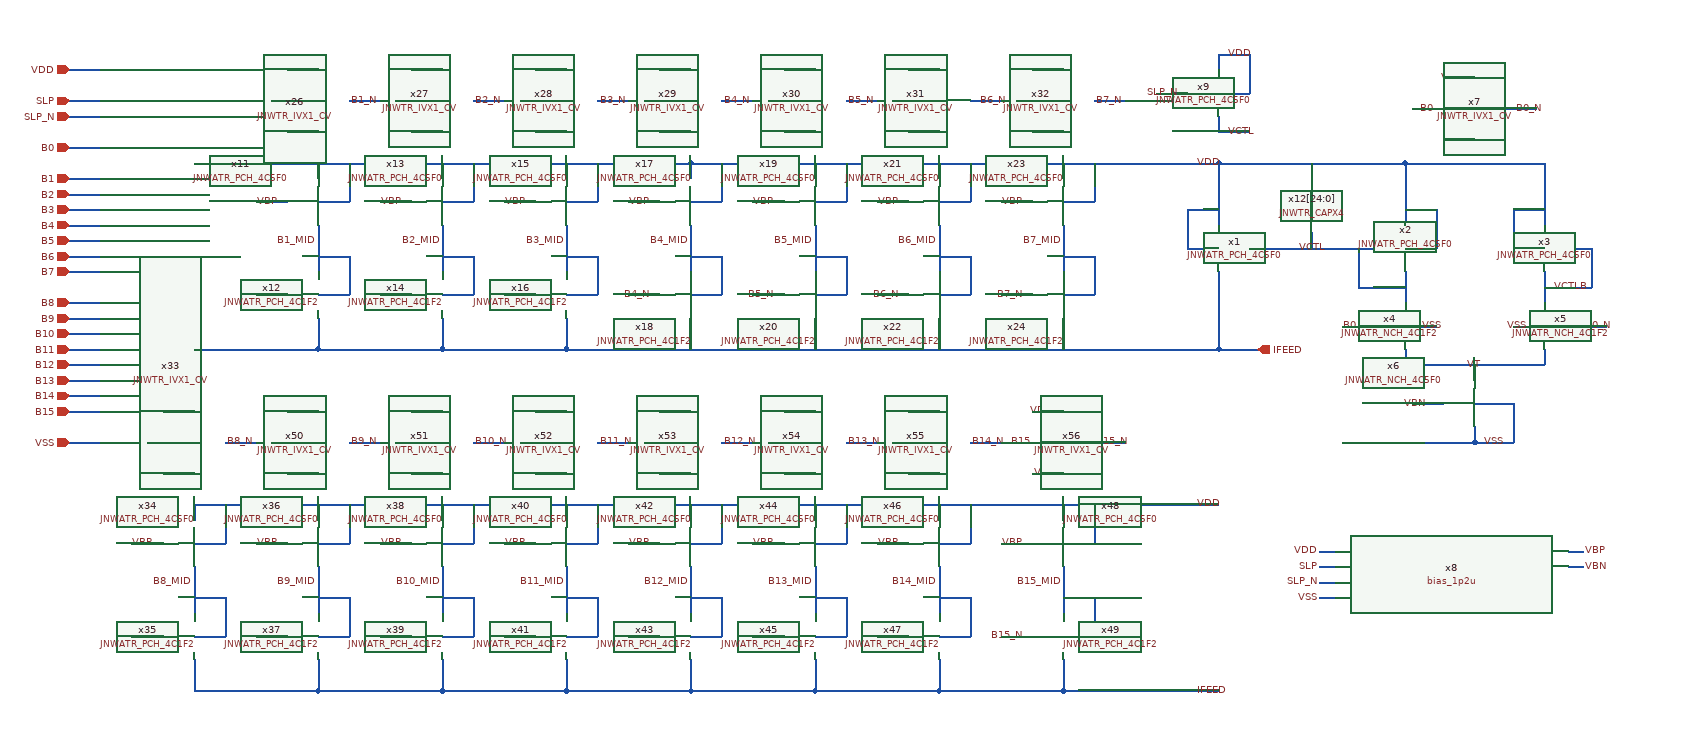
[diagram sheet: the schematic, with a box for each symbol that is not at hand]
v {xschem version=3.4.6 file_version=1.2}
G {}
K {}
V {}
S {}
E {}
N 920 330 960 330 {lab=VBP}
N 1000 280 1000 300 {lab=VDD}
N 1000 360 1000 420 {lab=B4_MID}
N 1000 480 1000 520 {lab=IFEED}
N 920 450 960 450 {lab=B4_N}
N 1000 330 1040 330 {lab=VDD}
N 1040 280 1040 330 {lab=VDD}
N 1000 450 1040 450 {lab=B4_MID}
N 1040 400 1040 450 {lab=B4_MID}
N 1000 400 1040 400 {lab=B4_MID}
N 1020 520 1180 520 {lab=IFEED}
N 1080 330 1120 330 {lab=VBP}
N 1160 280 1160 300 {lab=VDD}
N 1160 360 1160 420 {lab=B5_MID}
N 1160 480 1160 520 {lab=IFEED}
N 1080 450 1120 450 {lab=B5_N}
N 1160 330 1200 330 {lab=VDD}
N 1200 280 1200 330 {lab=VDD}
N 1160 450 1200 450 {lab=B5_MID}
N 1200 400 1200 450 {lab=B5_MID}
N 1160 400 1200 400 {lab=B5_MID}
N 1180 520 1340 520 {lab=IFEED}
N 1240 330 1280 330 {lab=VBP}
N 1320 280 1320 300 {lab=VDD}
N 1320 360 1320 420 {lab=B6_MID}
N 1320 480 1320 520 {lab=IFEED}
N 1240 450 1280 450 {lab=B6_N}
N 1320 330 1360 330 {lab=VDD}
N 1360 280 1360 330 {lab=VDD}
N 1320 450 1360 450 {lab=B6_MID}
N 1360 400 1360 450 {lab=B6_MID}
N 1320 400 1360 400 {lab=B6_MID}
N 1340 520 1500 520 {lab=IFEED}
N 1400 330 1440 330 {lab=VBP}
N 1480 280 1480 300 {lab=VDD}
N 1480 360 1480 420 {lab=B7_MID}
N 1480 480 1480 520 {lab=IFEED}
N 1400 450 1440 450 {lab=B7_N}
N 1480 330 1520 330 {lab=VDD}
N 1520 280 1520 330 {lab=VDD}
N 1480 450 1520 450 {lab=B7_MID}
N 1520 400 1520 450 {lab=B7_MID}
N 1480 400 1520 400 {lab=B7_MID}
N 1000 280 1680 280 {lab=VDD}
N 200 320 240 320 {lab=B2}
N 200 340 240 340 {lab=B3}
N 200 360 240 360 {lab=B4}
N 460 200 480 200 {lab=B1}
N 480 160 520 160 {lab=VDD}
N 480 240 520 240 {lab=VSS}
N 560 200 600 200 {lab=B1_N}
N 620 200 640 200 {lab=B2}
N 640 160 680 160 {lab=VDD}
N 640 240 680 240 {lab=VSS}
N 720 200 760 200 {lab=B2_N}
N 780 200 800 200 {lab=B3}
N 800 160 840 160 {lab=VDD}
N 800 240 840 240 {lab=VSS}
N 880 200 920 200 {lab=B3_N}
N 940 200 960 200 {lab=B4}
N 960 160 1000 160 {lab=VDD}
N 960 240 1000 240 {lab=VSS}
N 1040 200 1080 200 {lab=B4_N}
N 1810 800 1830 800 {lab=SLP}
N 2130 800 2150 800 {lab=VBN}
N 2130 780 2150 780 {lab=VBP}
N 1810 840 1830 840 {lab=VSS}
N 1810 780 1830 780 {lab=VDD}
N 1720 390 1880 390 {lab=VCTL}
N 1680 280 1680 360 {lab=VDD}
N 1500 520 1680 520 {lab=IFEED}
N 1800 370 1800 390 {lab=VCTL}
N 1800 280 1800 300 {lab=VDD}
N 1680 280 1920 280 {lab=VDD}
N 1920 280 1920 360 {lab=VDD}
N 1920 390 1960 390 {lab=VDD}
N 1960 340 1960 390 {lab=VDD}
N 1920 340 1960 340 {lab=VDD}
N 1860 390 1860 440 {lab=VCTL}
N 1860 440 1920 440 {lab=VCTL}
N 1920 420 1920 460 {lab=VCTL}
N 2140 390 2160 390 {lab=VCTLB}
N 2100 280 2100 360 {lab=VDD}
N 2060 390 2100 390 {lab=VDD}
N 2060 340 2060 390 {lab=VDD}
N 2160 390 2160 440 {lab=VCTLB}
N 2100 440 2160 440 {lab=VCTLB}
N 2100 420 2100 460 {lab=VCTLB}
N 1920 280 2100 280 {lab=VDD}
N 2060 340 2100 340 {lab=VDD}
N 1680 420 1680 520 {lab=IFEED}
N 2060 490 2100 490 {lab=VSS}
N 1920 490 1960 490 {lab=VSS}
N 1920 520 1920 540 {lab=VT}
N 2100 520 2100 540 {lab=VT}
N 1840 490 1880 490 {lab=B0}
N 2140 490 2180 490 {lab=B0_N}
N 2010 540 2010 560 {lab=VT}
N 2060 590 2060 640 {lab=VSS}
N 1640 390 1680 390 {lab=VDD}
N 1640 340 1640 390 {lab=VDD}
N 1640 340 1680 340 {lab=VDD}
N 2010 620 2010 640 {lab=VSS}
N 2010 590 2060 590 {lab=VSS}
N 2010 640 2060 640 {lab=VSS}
N 1930 590 1970 590 {lab=VBN}
N 1680 520 1730 520 {lab=IFEED}
N 200 200 240 200 {lab=SLP}
N 200 160 240 160 {lab=VDD}
N 200 640 240 640 {lab=VSS}
N 360 520 520 520 {lab=IFEED}
N 440 330 480 330 {lab=VBP}
N 520 280 520 300 {lab=VDD}
N 520 360 520 420 {lab=B1_MID}
N 520 480 520 520 {lab=IFEED}
N 440 450 480 450 {lab=B1_N}
N 520 330 560 330 {lab=VDD}
N 560 280 560 330 {lab=VDD}
N 520 450 560 450 {lab=B1_MID}
N 560 400 560 450 {lab=B1_MID}
N 520 400 560 400 {lab=B1_MID}
N 520 520 680 520 {lab=IFEED}
N 600 330 640 330 {lab=VBP}
N 680 280 680 300 {lab=VDD}
N 680 360 680 420 {lab=B2_MID}
N 680 480 680 520 {lab=IFEED}
N 600 450 640 450 {lab=B2_N}
N 680 330 720 330 {lab=VDD}
N 720 280 720 330 {lab=VDD}
N 680 450 720 450 {lab=B2_MID}
N 720 400 720 450 {lab=B2_MID}
N 680 400 720 400 {lab=B2_MID}
N 680 520 840 520 {lab=IFEED}
N 760 330 800 330 {lab=VBP}
N 840 280 840 300 {lab=VDD}
N 840 360 840 420 {lab=B3_MID}
N 840 480 840 520 {lab=IFEED}
N 760 450 800 450 {lab=B3_N}
N 840 330 880 330 {lab=VDD}
N 880 280 880 330 {lab=VDD}
N 840 450 880 450 {lab=B3_MID}
N 880 400 880 450 {lab=B3_MID}
N 840 400 880 400 {lab=B3_MID}
N 360 280 1000 280 {lab=VDD}
N 840 520 1020 520 {lab=IFEED}
N 200 380 240 380 {lab=B5}
N 200 400 240 400 {lab=B6}
N 200 420 240 420 {lab=B7}
N 1100 200 1120 200 {lab=B5}
N 1120 160 1160 160 {lab=VDD}
N 1120 240 1160 240 {lab=VSS}
N 1200 200 1240 200 {lab=B5_N}
N 1260 200 1280 200 {lab=B6}
N 1280 160 1320 160 {lab=VDD}
N 1280 240 1320 240 {lab=VSS}
N 1360 200 1400 200 {lab=B6_N}
N 1420 200 1440 200 {lab=B7}
N 1440 160 1480 160 {lab=VDD}
N 1440 240 1480 240 {lab=VSS}
N 1520 200 1560 200 {lab=B7_N}
N 1930 210 1970 210 {lab=B0}
N 1970 170 2010 170 {lab=VDD}
N 1970 250 2010 250 {lab=VSS}
N 2050 210 2090 210 {lab=B0_N}
N 200 260 240 260 {lab=B0}
N 200 480 240 480 {lab=B9}
N 200 500 240 500 {lab=B10}
N 200 520 240 520 {lab=B11}
N 200 540 240 540 {lab=B12}
N 200 460 240 460 {lab=B8}
N 200 560 240 560 {lab=B13}
N 200 580 240 580 {lab=B14}
N 200 600 240 600 {lab=B15}
N 1920 540 2100 540 {lab=VT}
N 920 770 960 770 {lab=VBP}
N 1000 720 1000 740 {lab=VDD}
N 1000 800 1000 860 {lab=B12_MID}
N 1000 920 1000 960 {lab=IFEED}
N 920 890 960 890 {lab=B12_N}
N 1000 770 1040 770 {lab=VDD}
N 1040 720 1040 770 {lab=VDD}
N 1000 890 1040 890 {lab=B12_MID}
N 1040 840 1040 890 {lab=B12_MID}
N 1000 840 1040 840 {lab=B12_MID}
N 1000 960 1160 960 {lab=IFEED}
N 1080 770 1120 770 {lab=VBP}
N 1160 720 1160 740 {lab=VDD}
N 1160 800 1160 860 {lab=B13_MID}
N 1160 920 1160 960 {lab=IFEED}
N 1080 890 1120 890 {lab=B13_N}
N 1160 770 1200 770 {lab=VDD}
N 1200 720 1200 770 {lab=VDD}
N 1160 890 1200 890 {lab=B13_MID}
N 1200 840 1200 890 {lab=B13_MID}
N 1160 840 1200 840 {lab=B13_MID}
N 1160 960 1320 960 {lab=IFEED}
N 1240 770 1280 770 {lab=VBP}
N 1320 720 1320 740 {lab=VDD}
N 1320 800 1320 860 {lab=B14_MID}
N 1320 920 1320 960 {lab=IFEED}
N 1240 890 1280 890 {lab=B14_N}
N 1320 770 1360 770 {lab=VDD}
N 1360 720 1360 770 {lab=VDD}
N 1320 890 1360 890 {lab=B14_MID}
N 1360 840 1360 890 {lab=B14_MID}
N 1320 840 1360 840 {lab=B14_MID}
N 1320 960 1480 960 {lab=IFEED}
N 1400 770 1440 770 {lab=VBP}
N 1480 720 1480 740 {lab=VDD}
N 1480 800 1480 860 {lab=B15_MID}
N 1480 920 1480 960 {lab=IFEED}
N 1400 890 1440 890 {lab=B15_N}
N 1480 770 1520 770 {lab=VDD}
N 1520 720 1520 770 {lab=VDD}
N 1480 890 1520 890 {lab=B15_MID}
N 1520 840 1520 890 {lab=B15_MID}
N 1480 840 1520 840 {lab=B15_MID}
N 1020 720 1680 720 {lab=VDD}
N 300 640 320 640 {lab=B8}
N 320 600 360 600 {lab=VDD}
N 320 680 360 680 {lab=VSS}
N 400 640 440 640 {lab=B8_N}
N 460 640 480 640 {lab=B9}
N 480 600 520 600 {lab=VDD}
N 480 680 520 680 {lab=VSS}
N 560 640 600 640 {lab=B9_N}
N 620 640 640 640 {lab=B10}
N 640 600 680 600 {lab=VDD}
N 640 680 680 680 {lab=VSS}
N 720 640 760 640 {lab=B10_N}
N 780 640 800 640 {lab=B11}
N 800 600 840 600 {lab=VDD}
N 800 680 840 680 {lab=VSS}
N 880 640 920 640 {lab=B11_N}
N 940 640 960 640 {lab=B12}
N 960 600 1000 600 {lab=VDD}
N 960 680 1000 680 {lab=VSS}
N 1040 640 1080 640 {lab=B12_N}
N 1480 960 1680 960 {lab=IFEED}
N 280 770 320 770 {lab=VBP}
N 360 720 360 740 {lab=VDD}
N 360 800 360 860 {lab=B8_MID}
N 360 920 360 960 {lab=IFEED}
N 280 890 320 890 {lab=B8_N}
N 360 770 400 770 {lab=VDD}
N 400 720 400 770 {lab=VDD}
N 360 890 400 890 {lab=B8_MID}
N 400 840 400 890 {lab=B8_MID}
N 360 840 400 840 {lab=B8_MID}
N 360 960 520 960 {lab=IFEED}
N 440 770 480 770 {lab=VBP}
N 520 720 520 740 {lab=VDD}
N 520 800 520 860 {lab=B9_MID}
N 520 920 520 960 {lab=IFEED}
N 440 890 480 890 {lab=B9_N}
N 520 770 560 770 {lab=VDD}
N 560 720 560 770 {lab=VDD}
N 520 890 560 890 {lab=B9_MID}
N 560 840 560 890 {lab=B9_MID}
N 520 840 560 840 {lab=B9_MID}
N 520 960 680 960 {lab=IFEED}
N 600 770 640 770 {lab=VBP}
N 680 720 680 740 {lab=VDD}
N 680 800 680 860 {lab=B10_MID}
N 680 920 680 960 {lab=IFEED}
N 600 890 640 890 {lab=B10_N}
N 680 770 720 770 {lab=VDD}
N 720 720 720 770 {lab=VDD}
N 680 890 720 890 {lab=B10_MID}
N 720 840 720 890 {lab=B10_MID}
N 680 840 720 840 {lab=B10_MID}
N 680 960 840 960 {lab=IFEED}
N 760 770 800 770 {lab=VBP}
N 840 720 840 740 {lab=VDD}
N 840 800 840 860 {lab=B11_MID}
N 840 920 840 960 {lab=IFEED}
N 760 890 800 890 {lab=B11_N}
N 840 770 880 770 {lab=VDD}
N 880 720 880 770 {lab=VDD}
N 840 890 880 890 {lab=B11_MID}
N 880 840 880 890 {lab=B11_MID}
N 840 840 880 840 {lab=B11_MID}
N 360 720 1020 720 {lab=VDD}
N 840 960 1000 960 {lab=IFEED}
N 1100 640 1120 640 {lab=B13}
N 1120 600 1160 600 {lab=VDD}
N 1120 680 1160 680 {lab=VSS}
N 1200 640 1240 640 {lab=B13_N}
N 1260 640 1280 640 {lab=B14}
N 1280 600 1320 600 {lab=VDD}
N 1280 680 1320 680 {lab=VSS}
N 1360 640 1400 640 {lab=B14_N}
N 1420 640 1440 640 {lab=B15}
N 1440 600 1480 600 {lab=VDD}
N 1440 680 1480 680 {lab=VSS}
N 1520 640 1560 640 {lab=B15_N}
N 200 300 240 300 {lab=B1}
N 1840 640 2010 640 {lab=VSS}
N 1680 240 1720 240 {lab=VCTL}
N 1680 140 1720 140 {lab=VDD}
N 1600 190 1640 190 {lab=SLP_N}
N 1680 190 1720 190 {lab=VDD}
N 1720 140 1720 190 {lab=VDD}
N 1680 220 1680 240 {lab=VCTL}
N 1680 140 1680 160 {lab=VDD}
N 1810 820 1830 820 {lab=SLP_N}
N 200 220 240 220 {lab=SLP_N}
C {devices/lab_wire.sym} 1430 450 0 0 {name=p3 sig_type=std_logic lab=B7_N
}
C {devices/lab_wire.sym} 1270 450 0 0 {name=p4 sig_type=std_logic lab=B6_N
}
C {devices/lab_wire.sym} 1110 450 0 0 {name=p5 sig_type=std_logic lab=B5_N
}
C {devices/lab_wire.sym} 950 450 0 0 {name=p6 sig_type=std_logic lab=B4_N
}
C {devices/ipin.sym} 200 160 0 0 {name=p14 lab=VDD}
C {devices/ipin.sym} 200 640 0 0 {name=p15 lab=VSS}
C {devices/ipin.sym} 200 320 0 0 {name=p17 lab=B2}
C {devices/ipin.sym} 200 340 0 0 {name=p19 lab=B3}
C {devices/ipin.sym} 200 360 0 0 {name=p20 lab=B4}
C {devices/lab_wire.sym} 510 240 2 1 {name=p26 sig_type=std_logic lab=VSS}
C {devices/lab_wire.sym} 510 160 0 0 {name=p27 sig_type=std_logic lab=VDD}
C {devices/lab_wire.sym} 670 240 2 1 {name=p30 sig_type=std_logic lab=VSS}
C {devices/lab_wire.sym} 670 160 0 0 {name=p31 sig_type=std_logic lab=VDD}
C {devices/lab_wire.sym} 830 240 2 1 {name=p34 sig_type=std_logic lab=VSS}
C {devices/lab_wire.sym} 830 160 0 0 {name=p35 sig_type=std_logic lab=VDD}
C {devices/lab_wire.sym} 990 240 2 1 {name=p38 sig_type=std_logic lab=VSS}
C {devices/lab_wire.sym} 990 160 0 0 {name=p39 sig_type=std_logic lab=VDD}
C {devices/lab_wire.sym} 800 200 0 0 {name=p25 sig_type=std_logic lab=B3}
C {devices/lab_wire.sym} 480 200 0 0 {name=p28 sig_type=std_logic lab=B1}
C {devices/lab_wire.sym} 960 200 0 0 {name=p29 sig_type=std_logic lab=B4}
C {devices/lab_wire.sym} 640 200 0 0 {name=p32 sig_type=std_logic lab=B2}
C {devices/lab_wire.sym} 880 200 0 1 {name=p36 sig_type=std_logic lab=B3_N}
C {devices/lab_wire.sym} 560 200 0 1 {name=p40 sig_type=std_logic lab=B1_N}
C {devices/lab_wire.sym} 1040 200 0 1 {name=p41 sig_type=std_logic lab=B4_N}
C {devices/lab_wire.sym} 720 200 0 1 {name=p45 sig_type=std_logic lab=B2_N}
C {devices/lab_wire.sym} 1110 330 0 0 {name=p9 sig_type=std_logic lab=VBP
}
C {devices/lab_wire.sym} 1270 330 0 0 {name=p8 sig_type=std_logic lab=VBP
}
C {devices/lab_wire.sym} 1430 330 0 0 {name=p10 sig_type=std_logic lab=VBP
}
C {devices/lab_wire.sym} 950 330 0 0 {name=p12 sig_type=std_logic lab=VBP
}
C {devices/ipin.sym} 200 200 0 0 {name=p33 lab=SLP}
C {devices/lab_wire.sym} 2150 780 0 1 {name=p13 sig_type=std_logic lab=VBP
}
C {devices/lab_wire.sym} 2150 800 0 1 {name=p21 sig_type=std_logic lab=VBN
}
C {JNW_TR_SKY130A/JNWTR_CAPX4.sym} 1800 360 0 0 {name=x12[24:0]}
C {devices/lab_wire.sym} 2150 490 0 1 {name=p1 sig_type=std_logic lab=B0_N}
C {devices/lab_wire.sym} 1860 490 0 0 {name=p2 sig_type=std_logic lab=B0}
C {devices/lab_wire.sym} 1950 590 0 0 {name=p11 sig_type=std_logic lab=VBN
}
C {devices/lab_wire.sym} 1820 390 2 1 {name=p42 sig_type=std_logic lab=VCTL
}
C {devices/lab_wire.sym} 2110 440 2 0 {name=p43 sig_type=std_logic lab=VCTLB
}
C {devices/lab_wire.sym} 2020 540 0 0 {name=p44 sig_type=std_logic lab=VT}
C {devices/lab_wire.sym} 1810 840 0 0 {name=p50 sig_type=std_logic lab=VSS
}
C {devices/lab_wire.sym} 1810 780 0 0 {name=p51 sig_type=std_logic lab=VDD
}
C {devices/opin.sym} 1730 520 0 0 {name=p54 lab=IFEED}
C {devices/lab_wire.sym} 2050 640 0 0 {name=p52 sig_type=std_logic lab=VSS
}
C {devices/lab_wire.sym} 1810 800 0 0 {name=p53 sig_type=std_logic lab=SLP
}
C {devices/lab_wire.sym} 790 450 0 0 {name=p55 sig_type=std_logic lab=B3_N
}
C {devices/lab_wire.sym} 630 450 0 0 {name=p56 sig_type=std_logic lab=B2_N
}
C {devices/lab_wire.sym} 470 450 0 0 {name=p57 sig_type=std_logic lab=B1_N

}
C {devices/lab_wire.sym} 470 330 0 0 {name=p59 sig_type=std_logic lab=VBP

}
C {devices/lab_wire.sym} 630 330 0 0 {name=p60 sig_type=std_logic lab=VBP
}
C {devices/lab_wire.sym} 790 330 0 0 {name=p61 sig_type=std_logic lab=VBP
}
C {devices/lab_wire.sym} 1650 280 0 1 {name=p67 sig_type=std_logic lab=VDD
}
C {devices/ipin.sym} 200 380 0 0 {name=p22 lab=B5}
C {devices/ipin.sym} 200 400 0 0 {name=p68 lab=B6}
C {devices/ipin.sym} 200 420 0 0 {name=p69 lab=B7}
C {devices/lab_wire.sym} 1150 240 2 1 {name=p70 sig_type=std_logic lab=VSS
}
C {devices/lab_wire.sym} 1150 160 0 0 {name=p71 sig_type=std_logic lab=VDD}
C {devices/lab_wire.sym} 1120 200 0 0 {name=p72 sig_type=std_logic lab=B5}
C {devices/lab_wire.sym} 1200 200 0 1 {name=p73 sig_type=std_logic lab=B5_N}
C {devices/lab_wire.sym} 1310 240 2 1 {name=p74 sig_type=std_logic lab=VSS}
C {devices/lab_wire.sym} 1310 160 0 0 {name=p75 sig_type=std_logic lab=VDD}
C {devices/lab_wire.sym} 1280 200 0 0 {name=p76 sig_type=std_logic lab=B6}
C {devices/lab_wire.sym} 1370 200 0 1 {name=p77 sig_type=std_logic lab=B6_N}
C {devices/lab_wire.sym} 1470 240 2 1 {name=p78 sig_type=std_logic lab=VSS}
C {devices/lab_wire.sym} 1470 160 0 0 {name=p79 sig_type=std_logic lab=VDD}
C {devices/lab_wire.sym} 1440 200 0 0 {name=p80 sig_type=std_logic lab=B7}
C {devices/lab_wire.sym} 1520 200 0 1 {name=p81 sig_type=std_logic lab=B7_N}
C {devices/lab_wire.sym} 2000 250 2 1 {name=p82 sig_type=std_logic lab=VSS}
C {devices/lab_wire.sym} 2000 170 0 0 {name=p83 sig_type=std_logic lab=VDD}
C {devices/lab_wire.sym} 1960 210 0 0 {name=p84 sig_type=std_logic lab=B0}
C {devices/lab_wire.sym} 2060 210 0 1 {name=p85 sig_type=std_logic lab=B0_N}
C {devices/ipin.sym} 200 260 0 0 {name=p86 lab=B0}
C {devices/ipin.sym} 200 480 0 0 {name=p139 lab=B9}
C {devices/ipin.sym} 200 500 0 0 {name=p145 lab=B10}
C {devices/ipin.sym} 200 520 0 0 {name=p147 lab=B11}
C {devices/ipin.sym} 200 540 0 0 {name=p165 lab=B12}
C {devices/ipin.sym} 200 460 0 0 {name=p166 lab=B8}
C {devices/ipin.sym} 200 560 0 0 {name=p167 lab=B13}
C {devices/ipin.sym} 200 580 0 0 {name=p168 lab=B14}
C {devices/ipin.sym} 200 600 0 0 {name=p169 lab=B15}
C {JNW_ATR_SKY130A/JNWATR_PCH_4C5F0.sym} 1720 390 0 1 {name=x1 }
C {JNW_ATR_SKY130A/JNWATR_PCH_4C5F0.sym} 1880 390 0 0 {name=x2 }
C {JNW_ATR_SKY130A/JNWATR_PCH_4C5F0.sym} 2140 390 0 1 {name=x3 }
C {JNW_ATR_SKY130A/JNWATR_NCH_4C1F2.sym} 1880 490 0 0 {name=x4 }
C {JNW_ATR_SKY130A/JNWATR_NCH_4C1F2.sym} 2140 490 0 1 {name=x5 }
C {JNW_ATR_SKY130A/JNWATR_NCH_4C5F0.sym} 1970 590 0 0 {name=x6 }
C {JNW_TR_SKY130A/JNWTR_IVX1_CV.sym} 1970 210 0 0 {name=x7 }
C {LELO_TORD_SKY130A/bias_1p2u.sym} 1980 810 0 0 {name=x8}
C {JNW_ATR_SKY130A/JNWATR_PCH_4C5F0.sym} 480 330 0 0 {name=x11 }
C {JNW_ATR_SKY130A/JNWATR_PCH_4C1F2.sym} 480 450 0 0 {name=x12 }
C {JNW_ATR_SKY130A/JNWATR_PCH_4C5F0.sym} 640 330 0 0 {name=x13 }
C {JNW_ATR_SKY130A/JNWATR_PCH_4C1F2.sym} 640 450 0 0 {name=x14 }
C {JNW_ATR_SKY130A/JNWATR_PCH_4C5F0.sym} 800 330 0 0 {name=x15 }
C {JNW_ATR_SKY130A/JNWATR_PCH_4C1F2.sym} 800 450 0 0 {name=x16 }
C {JNW_ATR_SKY130A/JNWATR_PCH_4C5F0.sym} 960 330 0 0 {name=x17 }
C {JNW_ATR_SKY130A/JNWATR_PCH_4C1F2.sym} 960 450 0 0 {name=x18 }
C {JNW_ATR_SKY130A/JNWATR_PCH_4C5F0.sym} 1120 330 0 0 {name=x19 }
C {JNW_ATR_SKY130A/JNWATR_PCH_4C1F2.sym} 1120 450 0 0 {name=x20 }
C {JNW_ATR_SKY130A/JNWATR_PCH_4C5F0.sym} 1280 330 0 0 {name=x21 }
C {JNW_ATR_SKY130A/JNWATR_PCH_4C1F2.sym} 1280 450 0 0 {name=x22 }
C {JNW_ATR_SKY130A/JNWATR_PCH_4C5F0.sym} 1440 330 0 0 {name=x23 }
C {JNW_ATR_SKY130A/JNWATR_PCH_4C1F2.sym} 1440 450 0 0 {name=x24 }
C {JNW_TR_SKY130A/JNWTR_IVX1_CV.sym} 480 200 0 0 {name=x26 }
C {JNW_TR_SKY130A/JNWTR_IVX1_CV.sym} 640 200 0 0 {name=x27 }
C {JNW_TR_SKY130A/JNWTR_IVX1_CV.sym} 800 200 0 0 {name=x28 }
C {JNW_TR_SKY130A/JNWTR_IVX1_CV.sym} 960 200 0 0 {name=x29 }
C {JNW_TR_SKY130A/JNWTR_IVX1_CV.sym} 1120 200 0 0 {name=x30 }
C {JNW_TR_SKY130A/JNWTR_IVX1_CV.sym} 1280 200 0 0 {name=x31 }
C {JNW_TR_SKY130A/JNWTR_IVX1_CV.sym} 1440 200 0 0 {name=x32 }
C {devices/lab_wire.sym} 1430 890 0 0 {name=p46 sig_type=std_logic lab=B15_N
}
C {devices/lab_wire.sym} 1270 890 0 0 {name=p47 sig_type=std_logic lab=B14_N
}
C {devices/lab_wire.sym} 1110 890 0 0 {name=p48 sig_type=std_logic lab=B13_N
}
C {devices/lab_wire.sym} 950 890 0 0 {name=p49 sig_type=std_logic lab=B12_N
}
C {devices/lab_wire.sym} 350 680 2 1 {name=p63 sig_type=std_logic lab=VSS}
C {devices/lab_wire.sym} 350 600 0 0 {name=p64 sig_type=std_logic lab=VDD}
C {devices/lab_wire.sym} 510 680 2 1 {name=p65 sig_type=std_logic lab=VSS}
C {devices/lab_wire.sym} 510 600 0 0 {name=p66 sig_type=std_logic lab=VDD}
C {devices/lab_wire.sym} 670 680 2 1 {name=p87 sig_type=std_logic lab=VSS}
C {devices/lab_wire.sym} 670 600 0 0 {name=p88 sig_type=std_logic lab=VDD}
C {devices/lab_wire.sym} 830 680 2 1 {name=p89 sig_type=std_logic lab=VSS
}
C {devices/lab_wire.sym} 830 600 0 0 {name=p90 sig_type=std_logic lab=VDD}
C {devices/lab_wire.sym} 990 680 2 1 {name=p91 sig_type=std_logic lab=VSS}
C {devices/lab_wire.sym} 990 600 0 0 {name=p92 sig_type=std_logic lab=VDD}
C {devices/lab_wire.sym} 320 640 0 0 {name=p93 sig_type=std_logic lab=B8}
C {devices/lab_wire.sym} 800 640 0 0 {name=p94 sig_type=std_logic lab=B11}
C {devices/lab_wire.sym} 480 640 0 0 {name=p95 sig_type=std_logic lab=B9}
C {devices/lab_wire.sym} 960 640 0 0 {name=p96 sig_type=std_logic lab=B12}
C {devices/lab_wire.sym} 640 640 0 0 {name=p97 sig_type=std_logic lab=B10}
C {devices/lab_wire.sym} 880 640 0 1 {name=p98 sig_type=std_logic lab=B11_N}
C {devices/lab_wire.sym} 400 640 0 1 {name=p99 sig_type=std_logic lab=B8_N}
C {devices/lab_wire.sym} 560 640 0 1 {name=p100 sig_type=std_logic lab=B9_N}
C {devices/lab_wire.sym} 1040 640 0 1 {name=p101 sig_type=std_logic lab=B12_N}
C {devices/lab_wire.sym} 720 640 0 1 {name=p102 sig_type=std_logic lab=B10_N}
C {devices/lab_wire.sym} 1110 770 0 0 {name=p103 sig_type=std_logic lab=VBP
}
C {devices/lab_wire.sym} 1270 770 0 0 {name=p104 sig_type=std_logic lab=VBP
}
C {devices/lab_wire.sym} 1430 770 0 0 {name=p105 sig_type=std_logic lab=VBP
}
C {devices/lab_wire.sym} 950 770 0 0 {name=p106 sig_type=std_logic lab=VBP
}
C {devices/lab_wire.sym} 790 890 0 0 {name=p107 sig_type=std_logic lab=B11_N
}
C {devices/lab_wire.sym} 630 890 0 0 {name=p108 sig_type=std_logic lab=B10_N
}
C {devices/lab_wire.sym} 470 890 0 0 {name=p109 sig_type=std_logic lab=B9_N
}
C {devices/lab_wire.sym} 310 890 0 0 {name=p110 sig_type=std_logic lab=B8_N
}
C {devices/lab_wire.sym} 470 770 0 0 {name=p111 sig_type=std_logic lab=VBP
}
C {devices/lab_wire.sym} 630 770 0 0 {name=p112 sig_type=std_logic lab=VBP
}
C {devices/lab_wire.sym} 790 770 0 0 {name=p113 sig_type=std_logic lab=VBP
}
C {devices/lab_wire.sym} 310 770 0 0 {name=p114 sig_type=std_logic lab=VBP
}
C {devices/lab_wire.sym} 1150 680 2 1 {name=p115 sig_type=std_logic lab=VSS}
C {devices/lab_wire.sym} 1150 600 0 0 {name=p116 sig_type=std_logic lab=VDD}
C {devices/lab_wire.sym} 1120 640 0 0 {name=p117 sig_type=std_logic lab=B13}
C {devices/lab_wire.sym} 1200 640 0 1 {name=p118 sig_type=std_logic lab=B13_N}
C {devices/lab_wire.sym} 1310 680 2 1 {name=p119 sig_type=std_logic lab=VSS
}
C {devices/lab_wire.sym} 1310 600 0 0 {name=p120 sig_type=std_logic lab=VDD}
C {devices/lab_wire.sym} 1280 640 0 0 {name=p121 sig_type=std_logic lab=B14}
C {devices/lab_wire.sym} 1360 640 0 1 {name=p122 sig_type=std_logic lab=B14_N}
C {devices/lab_wire.sym} 1470 680 2 1 {name=p123 sig_type=std_logic lab=VSS}
C {devices/lab_wire.sym} 1470 600 0 0 {name=p124 sig_type=std_logic lab=VDD}
C {devices/lab_wire.sym} 1440 640 0 0 {name=p125 sig_type=std_logic lab=B15}
C {devices/lab_wire.sym} 1520 640 0 1 {name=p126 sig_type=std_logic lab=B15_N}
C {JNW_TR_SKY130A/JNWTR_IVX1_CV.sym} 320 640 0 0 {name=x33 }
C {JNW_ATR_SKY130A/JNWATR_PCH_4C5F0.sym} 320 770 0 0 {name=x34 }
C {JNW_ATR_SKY130A/JNWATR_PCH_4C1F2.sym} 320 890 0 0 {name=x35 }
C {JNW_ATR_SKY130A/JNWATR_PCH_4C5F0.sym} 480 770 0 0 {name=x36 }
C {JNW_ATR_SKY130A/JNWATR_PCH_4C1F2.sym} 480 890 0 0 {name=x37 }
C {JNW_ATR_SKY130A/JNWATR_PCH_4C5F0.sym} 640 770 0 0 {name=x38 }
C {JNW_ATR_SKY130A/JNWATR_PCH_4C1F2.sym} 640 890 0 0 {name=x39 }
C {JNW_ATR_SKY130A/JNWATR_PCH_4C5F0.sym} 800 770 0 0 {name=x40 }
C {JNW_ATR_SKY130A/JNWATR_PCH_4C1F2.sym} 800 890 0 0 {name=x41 }
C {JNW_ATR_SKY130A/JNWATR_PCH_4C5F0.sym} 960 770 0 0 {name=x42 }
C {JNW_ATR_SKY130A/JNWATR_PCH_4C1F2.sym} 960 890 0 0 {name=x43 }
C {JNW_ATR_SKY130A/JNWATR_PCH_4C5F0.sym} 1120 770 0 0 {name=x44 }
C {JNW_ATR_SKY130A/JNWATR_PCH_4C1F2.sym} 1120 890 0 0 {name=x45 }
C {JNW_ATR_SKY130A/JNWATR_PCH_4C5F0.sym} 1280 770 0 0 {name=x46 }
C {JNW_ATR_SKY130A/JNWATR_PCH_4C1F2.sym} 1280 890 0 0 {name=x47 }
C {JNW_ATR_SKY130A/JNWATR_PCH_4C5F0.sym} 1440 770 0 0 {name=x48 }
C {JNW_ATR_SKY130A/JNWATR_PCH_4C1F2.sym} 1440 890 0 0 {name=x49 }
C {JNW_TR_SKY130A/JNWTR_IVX1_CV.sym} 480 640 0 0 {name=x50 }
C {JNW_TR_SKY130A/JNWTR_IVX1_CV.sym} 640 640 0 0 {name=x51 }
C {JNW_TR_SKY130A/JNWTR_IVX1_CV.sym} 800 640 0 0 {name=x52 }
C {JNW_TR_SKY130A/JNWTR_IVX1_CV.sym} 960 640 0 0 {name=x53 }
C {JNW_TR_SKY130A/JNWTR_IVX1_CV.sym} 1120 640 0 0 {name=x54 }
C {JNW_TR_SKY130A/JNWTR_IVX1_CV.sym} 1280 640 0 0 {name=x55 }
C {JNW_TR_SKY130A/JNWTR_IVX1_CV.sym} 1440 640 0 0 {name=x56 }
C {devices/lab_wire.sym} 1650 720 0 1 {name=p199 sig_type=std_logic lab=VDD
}
C {devices/lab_wire.sym} 1650 960 0 1 {name=p248 sig_type=std_logic lab=IFEED
}
C {devices/ipin.sym} 200 300 0 0 {name=p62 lab=B1}
C {devices/lab_wire.sym} 2080 490 2 1 {name=p7 sig_type=std_logic lab=VSS
}
C {devices/lab_wire.sym} 1940 490 2 0 {name=p16 sig_type=std_logic lab=VSS
}
C {devices/lab_wire.sym} 520 380 2 1 {name=p18 sig_type=std_logic lab=B1_MID
}
C {devices/lab_wire.sym} 680 380 2 1 {name=p23 sig_type=std_logic lab=B2_MID
}
C {devices/lab_wire.sym} 840 380 2 1 {name=p24 sig_type=std_logic lab=B3_MID
}
C {devices/lab_wire.sym} 1000 380 2 1 {name=p37 sig_type=std_logic lab=B4_MID
}
C {devices/lab_wire.sym} 1160 380 2 1 {name=p58 sig_type=std_logic lab=B5_MID
}
C {devices/lab_wire.sym} 1320 380 2 1 {name=p127 sig_type=std_logic lab=B6_MID
}
C {devices/lab_wire.sym} 1480 380 2 1 {name=p128 sig_type=std_logic lab=B7_MID
}
C {devices/lab_wire.sym} 360 820 2 1 {name=p129 sig_type=std_logic lab=B8_MID
}
C {devices/lab_wire.sym} 520 820 2 1 {name=p130 sig_type=std_logic lab=B9_MID
}
C {devices/lab_wire.sym} 680 820 2 1 {name=p131 sig_type=std_logic lab=B10_MID
}
C {devices/lab_wire.sym} 840 820 2 1 {name=p132 sig_type=std_logic lab=B11_MID
}
C {devices/lab_wire.sym} 1000 820 2 1 {name=p133 sig_type=std_logic lab=B12_MID
}
C {devices/lab_wire.sym} 1160 820 2 1 {name=p134 sig_type=std_logic lab=B13_MID
}
C {devices/lab_wire.sym} 1320 820 2 1 {name=p135 sig_type=std_logic lab=B14_MID
}
C {devices/lab_wire.sym} 1480 820 2 1 {name=p136 sig_type=std_logic lab=B15_MID
}
C {JNW_ATR_SKY130A/JNWATR_PCH_4C5F0.sym} 1640 190 0 0 {name=x9 }
C {devices/lab_wire.sym} 1630 190 0 0 {name=p137 sig_type=std_logic lab=SLP_N
}
C {devices/lab_wire.sym} 1690 140 0 1 {name=p138 sig_type=std_logic lab=VDD
}
C {devices/lab_wire.sym} 1690 240 2 0 {name=p140 sig_type=std_logic lab=VCTL
}
C {devices/lab_wire.sym} 1810 820 0 0 {name=p141 sig_type=std_logic lab=SLP_N
}
C {devices/ipin.sym} 200 220 0 0 {name=p142 lab=SLP_N}
